VERSION 5.7 ;
  NOWIREEXTENSIONATPIN ON ;
  DIVIDERCHAR "/" ;
  BUSBITCHARS "[]" ;
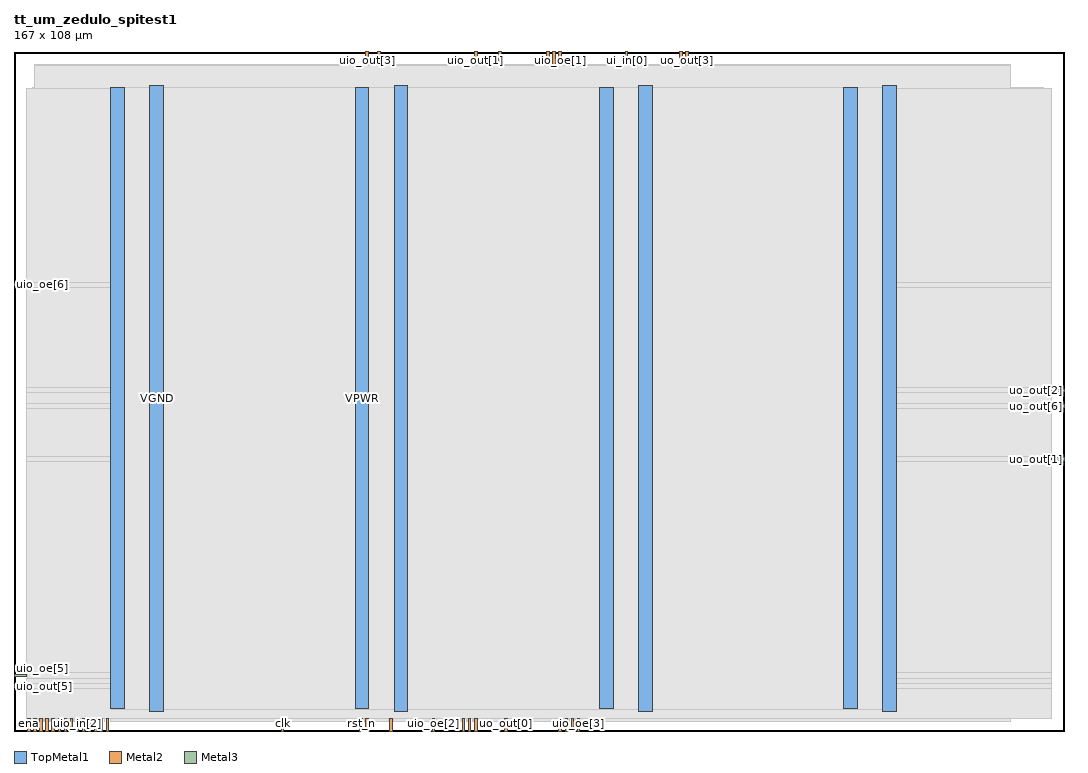
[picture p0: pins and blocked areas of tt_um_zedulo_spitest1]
MACRO tt_um_zedulo_spitest1
  CLASS BLOCK ;
  FOREIGN tt_um_zedulo_spitest1 ;
  ORIGIN 0.000 0.000 ;
  SIZE 167.000 BY 108.000 ;
  PIN VGND
    DIRECTION INOUT ;
    USE GROUND ;
    PORT
      LAYER TopMetal1 ;
        RECT 21.580 3.150 23.780 102.690 ;
    END
    PORT
      LAYER TopMetal1 ;
        RECT 60.450 3.150 62.650 102.690 ;
    END
    PORT
      LAYER TopMetal1 ;
        RECT 99.320 3.150 101.520 102.690 ;
    END
    PORT
      LAYER TopMetal1 ;
        RECT 138.190 3.150 140.390 102.690 ;
    END
  END VGND
  PIN VPWR
    DIRECTION INOUT ;
    USE POWER ;
    PORT
      LAYER TopMetal1 ;
        RECT 15.380 3.560 17.580 102.280 ;
    END
    PORT
      LAYER TopMetal1 ;
        RECT 54.250 3.560 56.450 102.280 ;
    END
    PORT
      LAYER TopMetal1 ;
        RECT 93.120 3.560 95.320 102.280 ;
    END
    PORT
      LAYER TopMetal1 ;
        RECT 131.990 3.560 134.190 102.280 ;
    END
  END VPWR
  PIN clk
    DIRECTION INPUT ;
    USE SIGNAL ;
    ANTENNAGATEAREA 2.901600 ;
    PORT
      LAYER Metal2 ;
        RECT 42.520 0.000 42.920 2.000 ;
    END
  END clk
  PIN ena
    DIRECTION INPUT ;
    USE SIGNAL ;
    PORT
      LAYER Metal2 ;
        RECT 2.200 0.000 2.600 2.000 ;
    END
  END ena
  PIN rst_n
    DIRECTION INPUT ;
    USE SIGNAL ;
    ANTENNAGATEAREA 0.180700 ;
    PORT
      LAYER Metal2 ;
        RECT 55.000 0.000 55.400 2.000 ;
    END
  END rst_n
  PIN ui_in[0]
    DIRECTION INPUT ;
    USE SIGNAL ;
    ANTENNAGATEAREA 0.180700 ;
    PORT
      LAYER Metal2 ;
        RECT 97.240 106.000 97.640 108.000 ;
    END
  END ui_in[0]
  PIN ui_in[1]
    DIRECTION INPUT ;
    USE SIGNAL ;
    ANTENNAGATEAREA 0.180700 ;
    PORT
      LAYER Metal2 ;
        RECT 72.280 0.000 72.680 2.000 ;
    END
  END ui_in[1]
  PIN ui_in[2]
    DIRECTION INPUT ;
    USE SIGNAL ;
    ANTENNAGATEAREA 0.180700 ;
    PORT
      LAYER Metal2 ;
        RECT 55.960 0.000 56.360 2.000 ;
    END
  END ui_in[2]
  PIN ui_in[3]
    DIRECTION INPUT ;
    USE SIGNAL ;
    PORT
      LAYER Metal2 ;
        RECT 3.160 0.000 3.560 2.000 ;
    END
  END ui_in[3]
  PIN ui_in[4]
    DIRECTION INPUT ;
    USE SIGNAL ;
    PORT
      LAYER Metal2 ;
        RECT 4.120 0.000 4.520 2.000 ;
    END
  END ui_in[4]
  PIN ui_in[5]
    DIRECTION INPUT ;
    USE SIGNAL ;
    PORT
      LAYER Metal2 ;
        RECT 5.080 0.000 5.480 2.000 ;
    END
  END ui_in[5]
  PIN ui_in[6]
    DIRECTION INPUT ;
    USE SIGNAL ;
    PORT
      LAYER Metal2 ;
        RECT 6.040 0.000 6.440 2.000 ;
    END
  END ui_in[6]
  PIN ui_in[7]
    DIRECTION INPUT ;
    USE SIGNAL ;
    PORT
      LAYER Metal2 ;
        RECT 7.000 0.000 7.400 2.000 ;
    END
  END ui_in[7]
  PIN uio_in[0]
    DIRECTION INPUT ;
    USE SIGNAL ;
    PORT
      LAYER Metal2 ;
        RECT 7.960 0.000 8.360 2.000 ;
    END
  END uio_in[0]
  PIN uio_in[1]
    DIRECTION INPUT ;
    USE SIGNAL ;
    PORT
      LAYER Metal2 ;
        RECT 8.920 0.000 9.320 2.000 ;
    END
  END uio_in[1]
  PIN uio_in[2]
    DIRECTION INPUT ;
    USE SIGNAL ;
    PORT
      LAYER Metal2 ;
        RECT 9.880 0.000 10.280 2.000 ;
    END
  END uio_in[2]
  PIN uio_in[3]
    DIRECTION INPUT ;
    USE SIGNAL ;
    PORT
      LAYER Metal2 ;
        RECT 10.840 0.000 11.240 2.000 ;
    END
  END uio_in[3]
  PIN uio_in[4]
    DIRECTION INPUT ;
    USE SIGNAL ;
    PORT
      LAYER Metal2 ;
        RECT 11.800 0.000 12.200 2.000 ;
    END
  END uio_in[4]
  PIN uio_in[5]
    DIRECTION INPUT ;
    USE SIGNAL ;
    PORT
      LAYER Metal2 ;
        RECT 12.760 0.000 13.160 2.000 ;
    END
  END uio_in[5]
  PIN uio_in[6]
    DIRECTION INPUT ;
    USE SIGNAL ;
    PORT
      LAYER Metal2 ;
        RECT 13.720 0.000 14.120 2.000 ;
    END
  END uio_in[6]
  PIN uio_in[7]
    DIRECTION INPUT ;
    USE SIGNAL ;
    PORT
      LAYER Metal2 ;
        RECT 14.680 0.000 15.080 2.000 ;
    END
  END uio_in[7]
  PIN uio_oe[0]
    DIRECTION OUTPUT ;
    USE SIGNAL ;
    ANTENNADIFFAREA 0.299200 ;
    PORT
      LAYER Metal2 ;
        RECT 105.880 106.000 106.280 108.000 ;
    END
  END uio_oe[0]
  PIN uio_oe[1]
    DIRECTION OUTPUT ;
    USE SIGNAL ;
    ANTENNADIFFAREA 0.299200 ;
    PORT
      LAYER Metal2 ;
        RECT 86.680 106.000 87.080 108.000 ;
    END
  END uio_oe[1]
  PIN uio_oe[2]
    DIRECTION OUTPUT ;
    USE SIGNAL ;
    ANTENNADIFFAREA 0.299200 ;
    PORT
      LAYER Metal2 ;
        RECT 66.520 0.000 66.920 2.000 ;
    END
  END uio_oe[2]
  PIN uio_oe[3]
    DIRECTION OUTPUT ;
    USE SIGNAL ;
    ANTENNADIFFAREA 0.299200 ;
    PORT
      LAYER Metal2 ;
        RECT 89.560 0.000 89.960 2.000 ;
    END
  END uio_oe[3]
  PIN uio_oe[4]
    DIRECTION OUTPUT ;
    USE SIGNAL ;
    ANTENNADIFFAREA 0.299200 ;
    PORT
      LAYER Metal2 ;
        RECT 86.680 0.000 87.080 2.000 ;
    END
  END uio_oe[4]
  PIN uio_oe[5]
    DIRECTION OUTPUT ;
    USE SIGNAL ;
    ANTENNADIFFAREA 0.299200 ;
    PORT
      LAYER Metal3 ;
        RECT 0.000 8.620 2.000 9.020 ;
    END
  END uio_oe[5]
  PIN uio_oe[6]
    DIRECTION OUTPUT ;
    USE SIGNAL ;
    ANTENNADIFFAREA 0.299200 ;
    PORT
      LAYER Metal3 ;
        RECT 0.000 70.780 2.000 71.180 ;
    END
  END uio_oe[6]
  PIN uio_oe[7]
    DIRECTION OUTPUT ;
    USE SIGNAL ;
    ANTENNADIFFAREA 0.299200 ;
    PORT
      LAYER Metal2 ;
        RECT 87.640 0.000 88.040 2.000 ;
    END
  END uio_oe[7]
  PIN uio_out[0]
    DIRECTION OUTPUT ;
    USE SIGNAL ;
    ANTENNADIFFAREA 0.299200 ;
    PORT
      LAYER Metal2 ;
        RECT 73.240 0.000 73.640 2.000 ;
    END
  END uio_out[0]
  PIN uio_out[1]
    DIRECTION OUTPUT ;
    USE SIGNAL ;
    ANTENNADIFFAREA 0.299200 ;
    PORT
      LAYER Metal2 ;
        RECT 73.240 106.000 73.640 108.000 ;
    END
  END uio_out[1]
  PIN uio_out[2]
    DIRECTION OUTPUT ;
    USE SIGNAL ;
    ANTENNADIFFAREA 0.299200 ;
    PORT
      LAYER Metal2 ;
        RECT 77.080 106.000 77.480 108.000 ;
    END
  END uio_out[2]
  PIN uio_out[3]
    DIRECTION OUTPUT ;
    USE SIGNAL ;
    ANTENNADIFFAREA 0.299200 ;
    PORT
      LAYER Metal2 ;
        RECT 55.960 106.000 56.360 108.000 ;
    END
  END uio_out[3]
  PIN uio_out[4]
    DIRECTION OUTPUT ;
    USE SIGNAL ;
    ANTENNADIFFAREA 0.299200 ;
    PORT
      LAYER Metal2 ;
        RECT 57.880 106.000 58.280 108.000 ;
    END
  END uio_out[4]
  PIN uio_out[5]
    DIRECTION OUTPUT ;
    USE SIGNAL ;
    ANTENNADIFFAREA 0.299200 ;
    PORT
      LAYER Metal3 ;
        RECT 0.000 6.940 2.000 7.340 ;
    END
  END uio_out[5]
  PIN uio_out[6]
    DIRECTION OUTPUT ;
    USE SIGNAL ;
    ANTENNADIFFAREA 0.299200 ;
    PORT
      LAYER Metal2 ;
        RECT 85.720 106.000 86.120 108.000 ;
    END
  END uio_out[6]
  PIN uio_out[7]
    DIRECTION OUTPUT ;
    USE SIGNAL ;
    ANTENNADIFFAREA 0.299200 ;
    PORT
      LAYER Metal2 ;
        RECT 88.600 0.000 89.000 2.000 ;
    END
  END uio_out[7]
  PIN uo_out[0]
    DIRECTION OUTPUT ;
    USE SIGNAL ;
    ANTENNADIFFAREA 0.708600 ;
    PORT
      LAYER Metal2 ;
        RECT 78.040 0.000 78.440 2.000 ;
    END
  END uo_out[0]
  PIN uo_out[1]
    DIRECTION OUTPUT ;
    USE SIGNAL ;
    ANTENNADIFFAREA 0.708600 ;
    PORT
      LAYER Metal3 ;
        RECT 165.000 43.060 167.000 43.460 ;
    END
  END uo_out[1]
  PIN uo_out[2]
    DIRECTION OUTPUT ;
    USE SIGNAL ;
    ANTENNADIFFAREA 0.708600 ;
    PORT
      LAYER Metal3 ;
        RECT 165.000 53.980 167.000 54.380 ;
    END
  END uo_out[2]
  PIN uo_out[3]
    DIRECTION OUTPUT ;
    USE SIGNAL ;
    ANTENNADIFFAREA 0.299200 ;
    PORT
      LAYER Metal2 ;
        RECT 106.840 106.000 107.240 108.000 ;
    END
  END uo_out[3]
  PIN uo_out[4]
    DIRECTION OUTPUT ;
    USE SIGNAL ;
    ANTENNADIFFAREA 0.299200 ;
    PORT
      LAYER Metal2 ;
        RECT 71.320 0.000 71.720 2.000 ;
    END
  END uo_out[4]
  PIN uo_out[5]
    DIRECTION OUTPUT ;
    USE SIGNAL ;
    ANTENNADIFFAREA 0.299200 ;
    PORT
      LAYER Metal2 ;
        RECT 84.760 106.000 85.160 108.000 ;
    END
  END uo_out[5]
  PIN uo_out[6]
    DIRECTION OUTPUT ;
    USE SIGNAL ;
    ANTENNADIFFAREA 0.708600 ;
    PORT
      LAYER Metal3 ;
        RECT 165.000 51.460 167.000 51.860 ;
    END
  END uo_out[6]
  PIN uo_out[7]
    DIRECTION OUTPUT ;
    USE SIGNAL ;
    ANTENNADIFFAREA 0.708600 ;
    PORT
      LAYER Metal2 ;
        RECT 59.800 0.000 60.200 2.000 ;
    END
  END uo_out[7]
  OBS
      LAYER GatPoly ;
        RECT 2.880 3.630 163.680 102.210 ;
      LAYER Metal1 ;
        RECT 2.880 3.560 163.680 102.280 ;
      LAYER Metal2 ;
        RECT 3.255 105.790 55.750 106.000 ;
        RECT 56.570 105.790 57.670 106.000 ;
        RECT 58.490 105.790 73.030 106.000 ;
        RECT 73.850 105.790 76.870 106.000 ;
        RECT 77.690 105.790 84.550 106.000 ;
        RECT 85.370 105.790 85.510 106.000 ;
        RECT 86.330 105.790 86.470 106.000 ;
        RECT 87.290 105.790 97.030 106.000 ;
        RECT 97.850 105.790 105.670 106.000 ;
        RECT 106.490 105.790 106.630 106.000 ;
        RECT 107.450 105.790 158.505 106.000 ;
        RECT 3.255 2.210 158.505 105.790 ;
        RECT 3.770 1.580 3.910 2.210 ;
        RECT 4.730 1.580 4.870 2.210 ;
        RECT 5.690 1.580 5.830 2.210 ;
        RECT 6.650 1.580 6.790 2.210 ;
        RECT 7.610 1.580 7.750 2.210 ;
        RECT 8.570 1.580 8.710 2.210 ;
        RECT 9.530 1.580 9.670 2.210 ;
        RECT 10.490 1.580 10.630 2.210 ;
        RECT 11.450 1.580 11.590 2.210 ;
        RECT 12.410 1.580 12.550 2.210 ;
        RECT 13.370 1.580 13.510 2.210 ;
        RECT 14.330 1.580 14.470 2.210 ;
        RECT 15.290 1.580 42.310 2.210 ;
        RECT 43.130 1.580 54.790 2.210 ;
        RECT 55.610 1.580 55.750 2.210 ;
        RECT 56.570 1.580 59.590 2.210 ;
        RECT 60.410 1.580 66.310 2.210 ;
        RECT 67.130 1.580 71.110 2.210 ;
        RECT 71.930 1.580 72.070 2.210 ;
        RECT 72.890 1.580 73.030 2.210 ;
        RECT 73.850 1.580 77.830 2.210 ;
        RECT 78.650 1.580 86.470 2.210 ;
        RECT 87.290 1.580 87.430 2.210 ;
        RECT 88.250 1.580 88.390 2.210 ;
        RECT 89.210 1.580 89.350 2.210 ;
        RECT 90.170 1.580 158.505 2.210 ;
      LAYER Metal3 ;
        RECT 2.000 71.390 165.000 102.160 ;
        RECT 2.210 70.570 165.000 71.390 ;
        RECT 2.000 54.590 165.000 70.570 ;
        RECT 2.000 53.770 164.790 54.590 ;
        RECT 2.000 52.070 165.000 53.770 ;
        RECT 2.000 51.250 164.790 52.070 ;
        RECT 2.000 43.670 165.000 51.250 ;
        RECT 2.000 42.850 164.790 43.670 ;
        RECT 2.000 9.230 165.000 42.850 ;
        RECT 2.210 8.410 165.000 9.230 ;
        RECT 2.000 7.550 165.000 8.410 ;
        RECT 2.210 6.730 165.000 7.550 ;
        RECT 2.000 2.000 165.000 6.730 ;
      LAYER Metal4 ;
        RECT 15.560 3.635 140.210 102.205 ;
      LAYER Metal5 ;
        RECT 15.515 3.470 140.255 102.370 ;
  END
END tt_um_zedulo_spitest1
END LIBRARY

